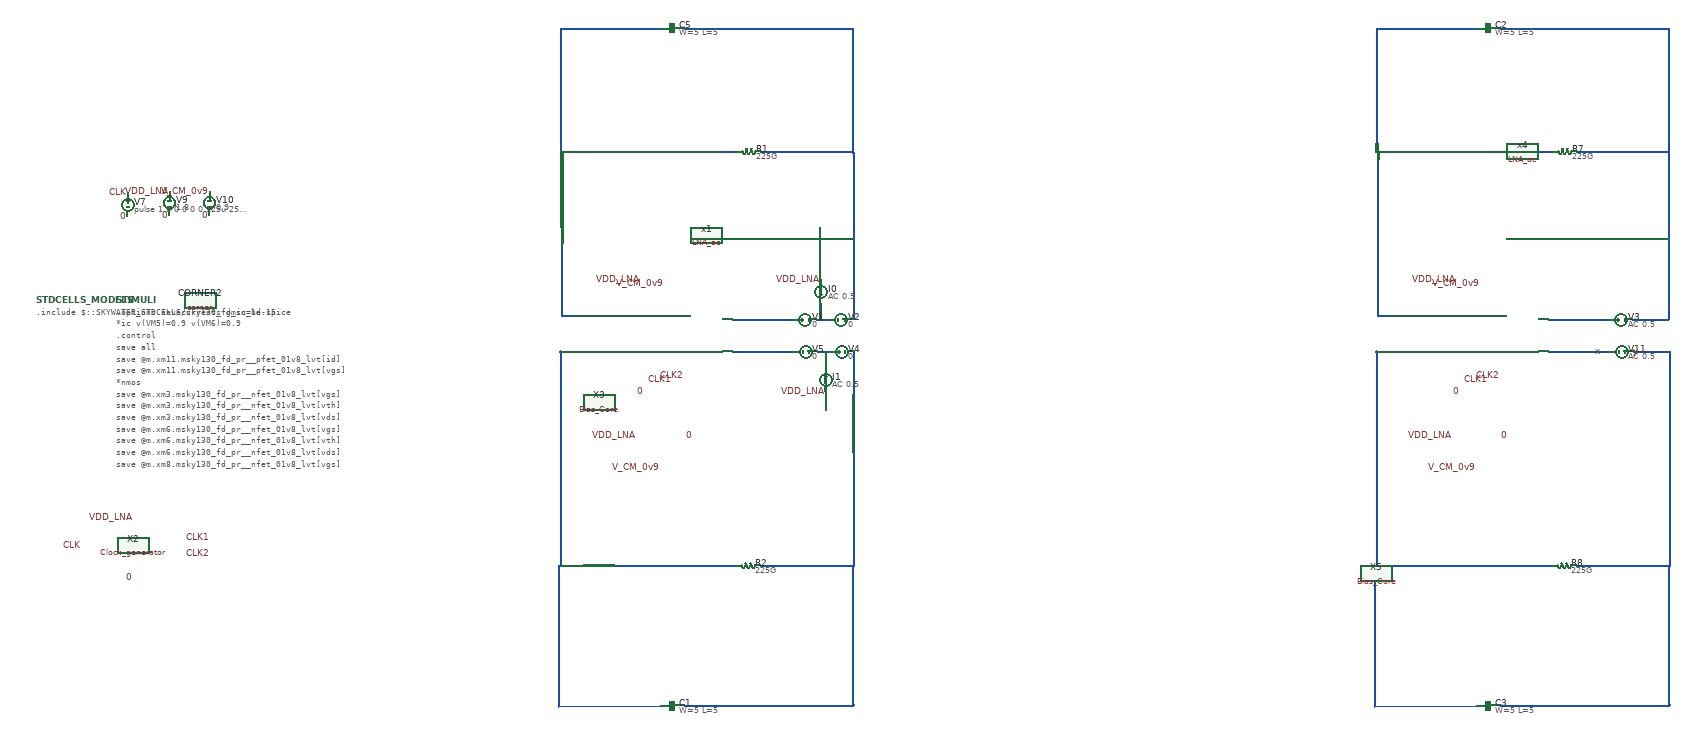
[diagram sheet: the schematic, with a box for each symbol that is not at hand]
v {xschem version=3.1.0 file_version=1.2
}
G {}
K {}
V {}
S {}
E {}
N 390 -170 540 -170 {
lab=#net1}
N 600 -170 630 -170 {
lab=#net2}
N 610 -210 610 -170 {
lab=#net2}
N 690 -577.5 690 -170 {
lab=#net3}
N -31.25 -898.75 208.75 -898.75 {
lab=#net4}
N -41.25 -898.75 -41.25 -588.75 {
lab=#net4}
N -41.25 -898.75 -31.25 -898.75 {
lab=#net4}
N 268.75 -898.75 648.75 -898.75 {
lab=#net3}
N 688.75 -898.75 688.75 -588.75 {
lab=#net3}
N 688.75 -588.75 690 -588.75 {
lab=#net3}
N 690 -588.75 690 -576.875 {
lab=#net3}
N 601.875 -90 631.875 -90 {
lab=#net5}
N 621.875 -90 621.875 -50 {
lab=#net5}
N 390 -90 541.875 -90 {
lab=#net6}
N 691.875 -90 691.875 161.875 {
lab=#net7}
N 691.875 161.25 691.875 402.5 {
lab=#net7}
N 458.75 444.375 690 444.375 {
lab=#net7}
N 690 444.375 691.25 444.375 {
lab=#net7}
N 691.25 444.375 691.875 444.375 {
lab=#net7}
N 691.875 402.5 691.875 444.375 {
lab=#net7}
N 75 444.375 94.375 444.375 {
lab=#net8}
N 24.375 444.375 75 444.375 {
lab=#net8}
N -1.875 444.375 24.375 444.375 {
lab=#net8}
N -40 444.375 -1.875 444.375 {
lab=#net8}
N -40 -90 -40 444.375 {
lab=#net8}
N -45 794.375 208.75 793.75 {
lab=#net8}
N -45 444.375 -45 794.375 {
lab=#net8}
N -45 444.375 -39.375 444.375 {
lab=#net8}
N 691.25 789.375 691.875 444.375 {
lab=#net7}
N 268.75 793.75 691.25 793.75 {
lab=#net7}
N 691.25 789.375 691.25 793.75 {
lab=#net7}
N -40 -90 -10 -90 {
lab=#net8}
N -41.25 -90 -40 -90 {
lab=#net8}
N -36.875 -180 -10 -180 {
lab=#net4}
N -41.25 -590 400 -590 {
lab=#net4}
N -36.25 -590 -36.25 -588.75 {
lab=#net4}
N 18.75 444.375 398.75 444.375 {
lab=#net8}
N 460 -590 648.75 -590 {
lab=#net3}
N 690 -370.625 691.875 -370.625 {
lab=#net3}
N 648.75 -898.75 688.75 -898.75 {
lab=#net3}
N -36.875 -590 -36.875 -180 {
lab=#net4}
N 2427.5 -170 2577.5 -170 {
lab=#net9}
N 2637.5 -170 2667.5 -170 {
lab=#net10}
N 2727.5 -577.5 2727.5 -170 {
lab=#net10}
N 2006.25 -898.75 2246.25 -898.75 {
lab=#net11}
N 1996.25 -898.75 1996.25 -588.75 {
lab=#net11}
N 1996.25 -898.75 2006.25 -898.75 {
lab=#net11}
N 2306.25 -898.75 2686.25 -898.75 {
lab=#net10}
N 2726.25 -898.75 2726.25 -588.75 {
lab=#net10}
N 2726.25 -588.75 2727.5 -588.75 {
lab=#net10}
N 2727.5 -588.75 2727.5 -576.875 {
lab=#net10}
N 2639.375 -90 2669.375 -90 {
lab=y}
N 2427.5 -90 2579.375 -90 {
lab=x}
N 2729.375 -90 2729.375 161.875 {
lab=y}
N 2496.25 444.375 2727.5 444.375 {
lab=y}
N 2727.5 444.375 2728.75 444.375 {
lab=y}
N 2728.75 444.375 2729.375 444.375 {
lab=y}
N 2729.375 402.5 2729.375 444.375 {
lab=y}
N 1997.5 -90 1997.5 444.375 {
lab=#net12}
N 1992.5 794.375 2246.25 793.75 {
lab=#net12}
N 1992.5 444.375 1992.5 794.375 {
lab=#net12}
N 2728.75 789.375 2729.375 444.375 {
lab=y}
N 2306.25 793.75 2728.75 793.75 {
lab=y}
N 2728.75 789.375 2728.75 793.75 {
lab=y}
N 1997.5 -90 2027.5 -90 {
lab=#net12}
N 1996.25 -90 1997.5 -90 {
lab=#net12}
N 2000.625 -180 2027.5 -180 {
lab=#net11}
N 1996.25 -590 2437.5 -590 {
lab=#net11}
N 2001.25 -590 2001.25 -588.75 {
lab=#net11}
N 2056.25 444.375 2436.25 444.375 {
lab=#net12}
N 2497.5 -590 2686.25 -590 {
lab=#net10}
N 2727.5 -370.625 2729.375 -370.625 {
lab=#net10}
N 2686.25 -898.75 2726.25 -898.75 {
lab=#net10}
N 2000.625 -590 2000.625 -180 {
lab=#net11}
N 2669.375 -90 2729.375 -90 {
lab=y}
N 2667.5 -170 2727.5 -170 {
lab=#net10}
N 648.75 -590 688.75 -590 {
lab=#net3}
N 2686.25 -590 2726.25 -590 {
lab=#net10}
N 1992.5 444.375 2056.25 444.375 {
lab=#net12}
N 2729.375 161.875 2729.375 402.5 {
lab=y}
C {LNA/LNA_ac.sym} 120 -130 0 0 {name=x1}
C {devices/vsource.sym} 570 -170 3 1 {name=V1 value=0}
C {devices/vsource.sym} 660 -170 1 0 {name=V2 value=0}
C {devices/isource.sym} 610 -240 0 0 {name=I0 value="AC 0.5"}
C {devices/vsource.sym} -1016.875 -461.25 0 0 {name=V9 value="1.8"}
C {devices/lab_pin.sym} -1016.875 -431.25 3 0 {name=p49 sig_type=std_logic lab=0}
C {devices/lab_pin.sym} -1016.875 -491.25 1 0 {name=p50 sig_type=std_logic lab=VDD_LNA}
C {devices/vsource.sym} -916.875 -461.25 0 0 {name=V10 value="0.9"}
C {devices/lab_pin.sym} -916.875 -431.25 3 0 {name=p51 sig_type=std_logic lab=0}
C {devices/lab_pin.sym} -916.875 -491.25 1 0 {name=p52 sig_type=std_logic lab=V_CM_0v9}
C {devices/vsource.sym} -1121.25 -457.5 0 1 {name=V7 value="pulse 1.8 0 0 0 0 125u 250u"}
C {devices/lab_pin.sym} -1121.25 -427.5 3 0 {name=p6 sig_type=std_logic lab=0}
C {devices/lab_pin.sym} -1121.25 -487.5 1 0 {name=p9 sig_type=std_logic lab=CLK}
C {LNA/Clock_generator.sym} -1106.875 393.75 0 0 {name=X2}
C {devices/lab_pin.sym} -1106.875 323.75 1 0 {name=p2 sig_type=std_logic lab=VDD_LNA}
C {devices/lab_pin.sym} -1106.875 473.75 3 0 {name=p3 sig_type=std_logic lab=0}
C {devices/lab_pin.sym} -1236.875 393.75 0 0 {name=p1 sig_type=std_logic lab=CLK}
C {devices/lab_pin.sym} -976.875 373.75 2 0 {name=p4 sig_type=std_logic lab=CLK1}
C {devices/lab_pin.sym} -976.875 413.75 2 0 {name=p5 sig_type=std_logic lab=CLK2}
C {devices/lab_pin.sym} 240 -20 3 0 {name=p7 sig_type=std_logic lab=CLK1}
C {devices/lab_pin.sym} 270 -30 3 0 {name=p8 sig_type=std_logic lab=CLK2}
C {LNA/Bias_Core.sym} 210 130 3 0 {name=X3}
C {devices/lab_pin.sym} 210 200 3 0 {name=p10 sig_type=std_logic lab=V_CM_0v9}
C {devices/lab_pin.sym} 150 120 0 0 {name=p11 sig_type=std_logic lab=VDD_LNA}
C {devices/lab_pin.sym} 160 -270 1 0 {name=p12 sig_type=std_logic lab=VDD_LNA}
C {devices/lab_pin.sym} 220 -260 1 0 {name=p13 sig_type=std_logic lab=V_CM_0v9}
C {devices/lab_pin.sym} 270 120 2 0 {name=p14 sig_type=std_logic lab=0}
C {devices/lab_pin.sym} 170 10 3 0 {name=p15 sig_type=std_logic lab=0}
C {devices/lab_pin.sym} 610 -270 1 0 {name=p17 sig_type=std_logic lab=VDD_LNA}
C {sky130_fd_pr/cap_mim_m3_2.sym} 238.75 -898.75 3 0 {name=C5 model=cap_mim_m3_2 W=5 L=5 MF=19 spiceprefix=X}
C {devices/vsource.sym} 661.875 -90 3 1 {name=V4 value=0}
C {devices/vsource.sym} 571.875 -90 1 0 {name=V5 value=0}
C {devices/isource.sym} 621.875 -20 2 0 {name=I1 value="AC 0.5"}
C {devices/lab_pin.sym} 621.875 10 3 0 {name=p18 sig_type=std_logic lab=VDD_LNA}
C {sky130_fd_pr/cap_mim_m3_2.sym} 238.75 793.75 3 0 {name=C1 model=cap_mim_m3_2 W=5 L=5 MF=19 spiceprefix=X}
C {devices/launcher.sym} -1100 0.625 0 0 {name=h1
descr="Annotate" 
tclcommand="set show_hidden_texts 1; xschem annotate_op"
}
C {sky130_fd_pr/corner.sym} -940 -219.375 0 0 {name=CORNER2 only_toplevel=false corner=ss
}
C {devices/launcher.sym} -1100 60.625 0 0 {name=h2 
descr="Simulate" 
tclcommand="xschem netlist; xschem simulate"}
C {devices/code.sym} -1150 -219.375 0 0 {name=STIMULI
only_toplevel=false
value="
.options savecurrents gmin=1e-15
*ic v(VM5)=0.9 v(VM6)=0.9
.control


save all

save @m.xm11.msky130_fd_pr__pfet_01v8_lvt[id]
save @m.xm11.msky130_fd_pr__pfet_01v8_lvt[vgs]


*nmos
save @m.xm3.msky130_fd_pr__nfet_01v8_lvt[vgs]
save @m.xm3.msky130_fd_pr__nfet_01v8_lvt[vth]
save @m.xm3.msky130_fd_pr__nfet_01v8_lvt[vds]

save @m.xm6.msky130_fd_pr__nfet_01v8_lvt[vgs]
save @m.xm6.msky130_fd_pr__nfet_01v8_lvt[vth]
save @m.xm6.msky130_fd_pr__nfet_01v8_lvt[vds]

save @m.xm8.msky130_fd_pr__nfet_01v8_lvt[vgs]
save @m.xm8.msky130_fd_pr__nfet_01v8_lvt[vth]
save @m.xm8.msky130_fd_pr__nfet_01v8_lvt[vds]

save @m.xm9.msky130_fd_pr__nfet_01v8_lvt[vgs]
save @m.xm9.msky130_fd_pr__nfet_01v8_lvt[vth]
save @m.xm9.msky130_fd_pr__nfet_01v8_lvt[vds]

save @m.xm18.msky130_fd_pr__nfet_01v8_lvt[vgs]
save @m.xm18.msky130_fd_pr__nfet_01v8_lvt[vth]
save @m.xm18.msky130_fd_pr__nfet_01v8_lvt[vds]

save @m.xm19.msky130_fd_pr__nfet_01v8_lvt[vgs]
save @m.xm19.msky130_fd_pr__nfet_01v8_lvt[vth]
save @m.xm19.msky130_fd_pr__nfet_01v8_lvt[vds]

save @m.xm25.msky130_fd_pr__nfet_01v8_lvt[vgs]
save @m.xm25.msky130_fd_pr__nfet_01v8_lvt[vth]
save @m.xm25.msky130_fd_pr__nfet_01v8_lvt[vds]

*pmos

save @m.xm1.msky130_fd_pr__pfet_01v8_lvt[vgs]
save @m.xm1.msky130_fd_pr__pfet_01v8_lvt[vth]
save @m.xm1.msky130_fd_pr__pfet_01v8_lvt[vds]


save @m.xm2.msky130_fd_pr__pfet_01v8_lvt[vgs]
save @m.xm2.msky130_fd_pr__pfet_01v8_lvt[vth]
save @m.xm2.msky130_fd_pr__pfet_01v8_lvt[vds]


save @m.xm10.msky130_fd_pr__pfet_01v8_lvt[vgs]
save @m.xm10.msky130_fd_pr__pfet_01v8_lvt[vth]
save @m.xm10.msky130_fd_pr__pfet_01v8_lvt[vds]

save @m.xm13.msky130_fd_pr__pfet_01v8_lvt[vgs]
save @m.xm13.msky130_fd_pr__pfet_01v8_lvt[vth]
save @m.xm13.msky130_fd_pr__pfet_01v8_lvt[vds]

save @m.xm4.msky130_fd_pr__pfet_01v8_lvt[vgs]
save @m.xm4.msky130_fd_pr__pfet_01v8_lvt[vth]
save @m.xm4.msky130_fd_pr__pfet_01v8_lvt[vds]

save @m.xm5.msky130_fd_pr__pfet_01v8_lvt[vgs]
save @m.xm5.msky130_fd_pr__pfet_01v8_lvt[vth]
save @m.xm5.msky130_fd_pr__pfet_01v8_lvt[vds]

save @m.xm16.msky130_fd_pr__pfet_01v8_lvt[vgs]
save @m.xm16.msky130_fd_pr__pfet_01v8_lvt[vth]
save @m.xm16.msky130_fd_pr__pfet_01v8_lvt[vds]

save @m.xm17.msky130_fd_pr__pfet_01v8_lvt[vgs]
save @m.xm17.msky130_fd_pr__pfet_01v8_lvt[vth]
save @m.xm17.msky130_fd_pr__pfet_01v8_lvt[vds]

save @m.xm3.msky130_fd_pr__pfet_01v8_lvt[vgs]
save @m.xm3.msky130_fd_pr__pfet_01v8_lvt[vth]
save @m.xm3.msky130_fd_pr__pfet_01v8_lvt[vds]

save @m.xm20.msky130_fd_pr__pfet_01v8_lvt[vgs]
save @m.xm20.msky130_fd_pr__pfet_01v8_lvt[vth]
save @m.xm20.msky130_fd_pr__pfet_01v8_lvt[vds]

save @m.xm2.msky130_fd_pr__pfet_01v8_lvt[vgs]
save @m.xm2.msky130_fd_pr__pfet_01v8_lvt[vth]
save @m.xm2.msky130_fd_pr__pfet_01v8_lvt[vds]

save @m.xm21.msky130_fd_pr__pfet_01v8_lvt[vgs]
save @m.xm21.msky130_fd_pr__pfet_01v8_lvt[vth]
save @m.xm21.msky130_fd_pr__pfet_01v8_lvt[vds]

save @m.xm7.msky130_fd_pr__nfet_01v8_lvt[vth]

save @m.xm1.msky130_fd_pr__pfet_01v8[vgs]

save @m.xm1.msky130_fd_pr__nfet_01v8_lvt[gm]


save @m.xm1.msky130_fd_pr__nfet_01v8_lvt[gds]
save @m.xm2.msky130_fd_pr__pfet_01v8_lvt[gm]

save @m.xm23.msky130_fd_pr__nfet_01v8[cgs]
save @m.xm4.msky130_fd_pr__pfet_01v8[cgs]
save @m.xm2.msky130_fd_pr__pfet_01v8_lvt[cgs]



save @m.xm2.msky130_fd_pr__pfet_01v8_lvt[gds]


op
write Stability_middlebrook.raw
*set appendwrite


.endc
.control



*tran 50u 1500m
*save all
*plot v(Outp)-v(outn)



ac dec 10 0.1 1000k
let Gi=I(V1)/I(V2)
let Gv=-V(x)/V(y)
let MB=(Gi*Gv-1)/(Gi+Gv+2)
let phase=180*cph(MB)/pi
plot db(MB) phase


.endc



"}
C {devices/code.sym} -1350 -219.375 0 0 {name=STDCELLS_MODELS
only_toplevel=true
format="tcleval( @value )"
value="
.include $::SKYWATER_STDCELLS/sky130_fd_sc_hd.spice
"
spice_ignore=false}
C {devices/res.sym} 430 -590 1 0 {name=R1
value=225G
footprint=1206
device=resistor
m=1}
C {devices/res.sym} 428.75 444.375 1 0 {name=R2
value=225G
footprint=1206
device=resistor
m=1}
C {devices/vsource.sym} 2607.5 -170 3 1 {name=V3 value="AC 0.5"}
C {devices/lab_pin.sym} 2277.5 -20 3 0 {name=p22 sig_type=std_logic lab=CLK1}
C {devices/lab_pin.sym} 2307.5 -30 3 0 {name=p23 sig_type=std_logic lab=CLK2}
C {LNA/Bias_Core.sym} 2247.5 130 3 0 {name=X5}
C {devices/lab_pin.sym} 2247.5 200 3 0 {name=p24 sig_type=std_logic lab=V_CM_0v9}
C {devices/lab_pin.sym} 2187.5 120 0 0 {name=p25 sig_type=std_logic lab=VDD_LNA}
C {devices/lab_pin.sym} 2197.5 -270 1 0 {name=p26 sig_type=std_logic lab=VDD_LNA}
C {devices/lab_pin.sym} 2257.5 -260 1 0 {name=p27 sig_type=std_logic lab=V_CM_0v9}
C {devices/lab_pin.sym} 2307.5 120 2 0 {name=p28 sig_type=std_logic lab=0}
C {devices/lab_pin.sym} 2207.5 10 3 0 {name=p29 sig_type=std_logic lab=0}
C {sky130_fd_pr/cap_mim_m3_2.sym} 2276.25 -898.75 3 0 {name=C2 model=cap_mim_m3_2 W=5 L=5 MF=19 spiceprefix=X}
C {devices/vsource.sym} 2609.375 -90 1 0 {name=V11 value="AC 0.5"}
C {sky130_fd_pr/cap_mim_m3_2.sym} 2276.25 793.75 3 0 {name=C3 model=cap_mim_m3_2 W=5 L=5 MF=19 spiceprefix=X}
C {devices/res.sym} 2467.5 -590 1 0 {name=R7
value=225G
footprint=1206
device=resistor
m=1}
C {devices/res.sym} 2466.25 444.375 1 0 {name=R8
value=225G
footprint=1206
device=resistor
m=1}
C {devices/lab_pin.sym} 2559.375 -90 3 0 {name=p30 sig_type=std_logic lab=x}
C {devices/lab_pin.sym} 2655 -90 3 0 {name=p31 sig_type=std_logic lab=y}
C {LNA/LNA_ac.sym} 2157.5 -130 0 0 {name=x4}
